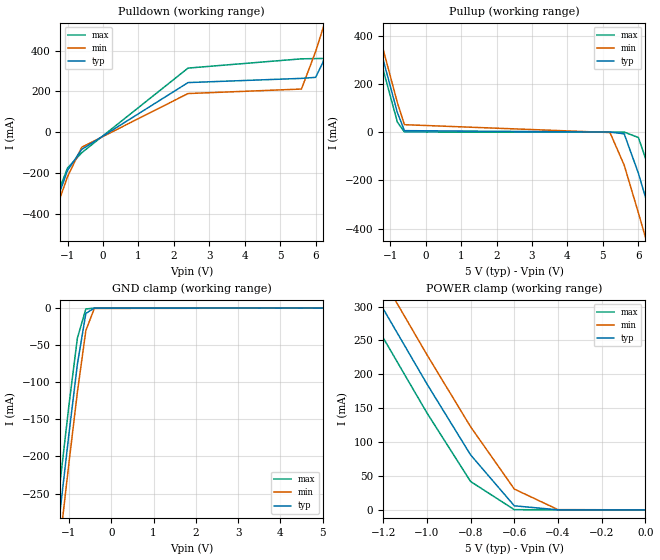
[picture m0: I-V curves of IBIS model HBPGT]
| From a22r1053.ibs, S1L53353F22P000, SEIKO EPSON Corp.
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[Model]   HBPGT
Model_type   I/O
Polarity   Non-Inverting
Vinh=2.0V
Vinl=0.8V
|   typ   min   max
C_comp   5.0pF   4.0pF   6.0pF
|   typ   min   max
[Voltage range]   5.0   4.75   5.25
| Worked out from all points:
|   slope of the pulldown table from 0 to 0.75 V, typ, clamps not added: 7.51 ohm
|   GND clamp passes 1 mA (typ) near -0.43 V on its own axis
|   POWER clamp passes 1 mA (typ) near -0.43 V on its own axis
[Pulldown]
|   Voltage   I(typ)   I(min)   I(max)
-5V       -2.263A    -2.296A    -2.23A
-1.8V     -581.9mA   -619.1mA   -545.8mA
-1.6V     -479.3mA   -516.5mA   -443.7mA
-1V       -187.9mA   -218.7mA   -176.5mA
-600mV    -85.03mA   -74.34mA   -101.4mA
2.4V      243mA      189.2mA    314.2mA
5.6V      263.6mA    211.3mA    359.6mA
6V        268.8mA    395.6mA    360.8mA
6.2V      340.2mA    505.4mA    361.4mA
6.4V      444.4mA    617.9mA    362.3mA
7V        782.5mA    961.5mA    609.6mA
10V       2.536A     2.714A     2.361A
[Pullup]
|   Voltage   I(typ)   I(min)   I(max)
-5V       2.513A     2.55A      2.477A
-1.6V     524.3mA    566.8mA    482.3mA
-1.4V     409.9mA    452.7mA    367.4mA
-800mV    81.11mA    122.6mA    41.82mA
-600mV    5.968mA    30.7mA     281.7uA
5.2V      -276.9nA   -1.829mA   -10.26nA
5.6V      -7.115mA   -136.8mA   -4.336uA
6V        -170mA     -334.1mA   -22.32mA
6.2V      -269.5mA   -435.9mA   -107.4mA
6.6V      -474.2mA   -641.9mA   -307.1mA
7V        -681.8mA   -849.8mA   -513.9mA
10V       -2.262A    -2.427A    -2.096A
[GND_clamp]
|   Voltage   I(typ)   I(min)   I(max)
-5V       -2.262A    -2.295A    -2.229A
-1.4V     -371.3mA   -410.3mA   -332.8mA
-1.2V     -269.6mA   -308.9mA   -230.8mA
-1V       -170.1mA   -209.2mA   -131.4mA
-800mV    -75.86mA   -113.5mA   -40.55mA
-600mV    -7.118mA   -30.46mA   -1.232mA
-400mV    -61.96uA   -470.6uA   -20.18uA
5V        12.59nA    3.448uA    11.52nA
[POWER_clamp]
|   Voltage   I(typ)   I(min)   I(max)
-5V       2.513A     2.55A      2.477A
-1.4V     409.9mA    452.7mA    367.4mA
-1.2V     296.7mA    339.9mA    253.9mA
-1V       185.9mA    229mA      143.2mA
-800mV    81.11mA    122.6mA    41.82mA
-600mV    5.968mA    30.7mA     281.7uA
-400mV    15.71uA    326.5uA    2.39uA
0V        12.59nA    24.71nA    12.62nA
[Ramp]
|   V_typ   V_min   V_max
dV/dt_r   3.00/0.43n   2.85/0.58n   3.15/0.30n
dV/dt_f   3.00/0.25n   2.85/0.33n   3.15/0.19n
R_load = 5000
